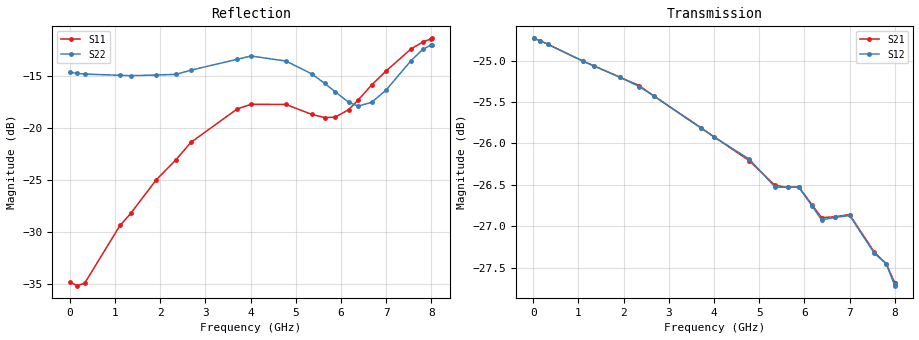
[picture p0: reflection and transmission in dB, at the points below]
! DEVICE ID: PE43712
! File Path: z:\PE43713\PE43713_CHAR_NOM_04292014\AMB\3p300\LS_ATT_23p50dB\PE43713_AMB_3p300V_3p000V_0p000V_LS_ATT_23p50dB_S2P_SN_10_A0139A.s2p
! Serial: 10
! Lot: A0139A
! Temp: 25C
! VDD: 3.300
! VSS: 0.000
! Control_Hi: 3.000
! Control_Lo: 0.000
! Attenuation Step: 23.50dB
! Port 1: RF1
! Port 2: RF2
! ThroughPath:1-2
! IDD: 0.0001472638
! ISS: -1.794e-007
#  Hz  S  RI  R  50
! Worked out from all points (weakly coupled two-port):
!   801 points, 10 MHz to 8.01 GHz, reference 50 ohm
!   highest |S21| = -24.74 dB at 10 MHz (marker M1); lowest = -27.7 dB at 8 GHz (marker M2)
!   lowest |S11| = -35.2 dB at 160 MHz (marker M3), VSWR 1.04, Z = 48.4 + j0.523 ohm
!   |S11| at or under -10 dB: start of sweep to end of sweep
!   |S22| runs from -17.9 to -11.9 dB; largest |S21 - S12| = 0.00022
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1e7  -0.018 0.000673  0.058 -0.000243  0.058 -0.000241  -0.1858 0.00118
1.6e8  -0.0165 0.00541  0.0577 -0.00344  0.0577 -0.00342  -0.1836 0.0117
3.3e8  -0.015 0.0097  0.0571 -0.00693  0.0571 -0.00686  -0.1812 0.0213
1.11e9  -0.01 0.0324  0.0521 -0.021  0.0521 -0.021  -0.1671 0.0667
1.35e9  -0.00643 0.0383  0.05 -0.0248  0.05 -0.0248  -0.1611 0.0785
1.91e9  0.00506 0.056  0.0441 -0.0328  0.0441 -0.0328  -0.1424 0.111
2.35e9  0.0169 0.0684  0.0385 -0.0383  0.0384 -0.0383  -0.1244 0.1327
2.68e9  0.0272 0.081  0.0339 -0.0414  0.0339 -0.0414  -0.1104 0.1553
3.71e9  0.0448 0.1157  0.0179 -0.048  0.0178 -0.048  -0.0837 0.1982
4.01e9  0.0473 0.1214  0.0132 -0.0488  0.0132 -0.0488  -0.0823 0.2072
4.78e9  0.0543 0.1183  0.00167 -0.0489  0.00172 -0.049  -0.0674 0.1998
5.35e9  0.0686 0.0943  -0.00593 -0.0469  -0.00592 -0.0468  -0.0507 0.1758
5.64e9  0.08 0.0791  -0.00939 -0.0462  -0.00937 -0.0462  -0.032 0.1613
5.87e9  0.0908 0.0671  -0.0129 -0.0454  -0.0128 -0.0454  -0.013 0.1494
6.17e9  0.1094 0.056  -0.0174 -0.0426  -0.0172 -0.0426  0.0167 0.1322
6.38e9  0.1263 0.0521  -0.0188 -0.0411  -0.0187 -0.041  0.0412 0.121
6.68e9  0.155 0.0465  -0.0221 -0.0395  -0.022 -0.0395  0.0783 0.1078
7e9  0.1833 0.0458  -0.0263 -0.037  -0.0262 -0.037  0.113 0.103
7.55e9  0.2356 0.0518  -0.0312 -0.0297  -0.0311 -0.0297  0.1792 0.1131
7.81e9  0.2537 0.0581  -0.0326 -0.0271  -0.0326 -0.0271  0.2067 0.1218
8e9  0.2633 0.0627  -0.033 -0.0248  -0.0328 -0.0248  0.2194 0.1251
8.01e9  0.2638 0.0633  -0.033 -0.0248  -0.0329 -0.0248  0.2201 0.1251
